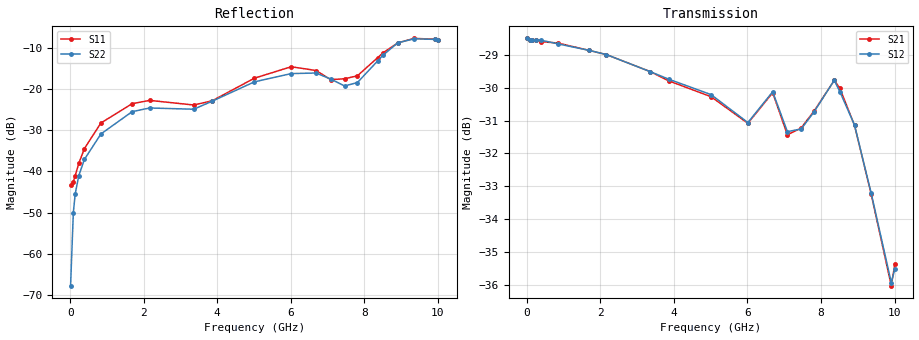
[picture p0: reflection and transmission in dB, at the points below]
! Device ID: PE43705
! Serial: 1
! Insertion: A
! Impedance: 50 ohm
! Temp: 25C
! VDD: 3.400V
! Attenuation Step: 27.50dB
#  Hz  S  RI  R  50
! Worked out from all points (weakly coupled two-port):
!   401 points, 10 MHz to 10.01 GHz, reference 50 ohm
!   highest |S21| = -28.50 dB at 10 MHz (marker M1); lowest = -36.0 dB at 9.91 GHz (marker M2)
!   lowest |S11| = -43.3 dB at 10 MHz (marker M3), VSWR 1.01, Z = 49.3 + j0.0463 ohm
!   |S11| at or under -10 dB: start of sweep to 8.691 GHz
!   |S22| runs from -67.7 to -7.8 dB; largest |S21 - S12| = 0.00062
!   S11 on the Smith chart (normalised r, x): 10 MHz: 0.99, +0.00; 7.46 GHz: 0.82, +0.16; 8.51 GHz: 0.82, +0.48; 9.36 GHz: 0.54, +0.48; 10.01 GHz: 0.48, +0.26
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1e7  -0.00684 0.000469  0.0376 -0.000175  0.0376 -9.34e-05  -7.47e-05 0.000404
8.5e7  -0.00659 0.00352  0.0374 -0.000865  0.0374 -0.000852  0.000463 0.00313
1.35e8  -0.00664 0.00589  0.0374 -0.00129  0.0374 -0.00132  0.000381 0.0053
2.35e8  -0.00766 0.00993  0.0373 -0.0023  0.0373 -0.00225  -0.000415 0.00888
3.85e8  -0.0104 0.0157  0.037 -0.00349  0.0372 -0.0035  -0.00303 0.0136
8.35e8  -0.0282 0.0263  0.0362 -0.00763  0.0361 -0.00759  -0.0183 0.0217
1.685e9  -0.064 0.0164  0.0331 -0.0143  0.0331 -0.0143  -0.0516 0.0117
2.16e9  -0.0724 0.00284  0.0308 -0.0177  0.0308 -0.0177  -0.0586 0.000743
3.36e9  -0.0636 0.00313  0.0233 -0.024  0.0234 -0.0239  -0.0564 0.00485
3.86e9  -0.0668 0.0258  0.0201 -0.0254  0.0204 -0.0254  -0.0679 0.0202
5.01e9  -0.1035 0.0861  0.0141 -0.0272  0.0144 -0.0273  -0.1058 0.0599
6.01e9  -0.1561 0.0999  0.00845 -0.0266  0.00869 -0.0266  -0.1327 0.0763
6.685e9  -0.147 0.0789  0.00592 -0.0305  0.00596 -0.0306  -0.1384 0.0709
7.085e9  -0.1139 0.0612  0.000458 -0.0268  0.000419 -0.0271  -0.1082 0.0746
7.46e9  -0.093 0.0942  0.00172 -0.0274  0.00176 -0.0273  -0.0713 0.0816
7.81e9  -0.0491 0.1352  0.00154 -0.0291  0.00168 -0.029  -0.0464 0.1097
8.36e9  -0.0168 0.2378  -0.00688 -0.0317  -0.007 -0.0317  -0.0332 0.2151
8.51e9  -0.026 0.2725  -0.00985 -0.03  -0.00954 -0.0297  -0.0419 0.2532
8.91e9  -0.0803 0.352  -0.0135 -0.0242  -0.0134 -0.0243  -0.1029 0.3465
9.36e9  -0.1813 0.3668  -0.0126 -0.0178  -0.0123 -0.0181  -0.1961 0.3541
9.91e9  -0.3011 0.2624  -0.00426 -0.0152  -0.00455 -0.0153  -0.3278 0.225
1.001e10  -0.314 0.2278  -0.0029 -0.0168  -0.00295 -0.0165  -0.3442 0.1856
